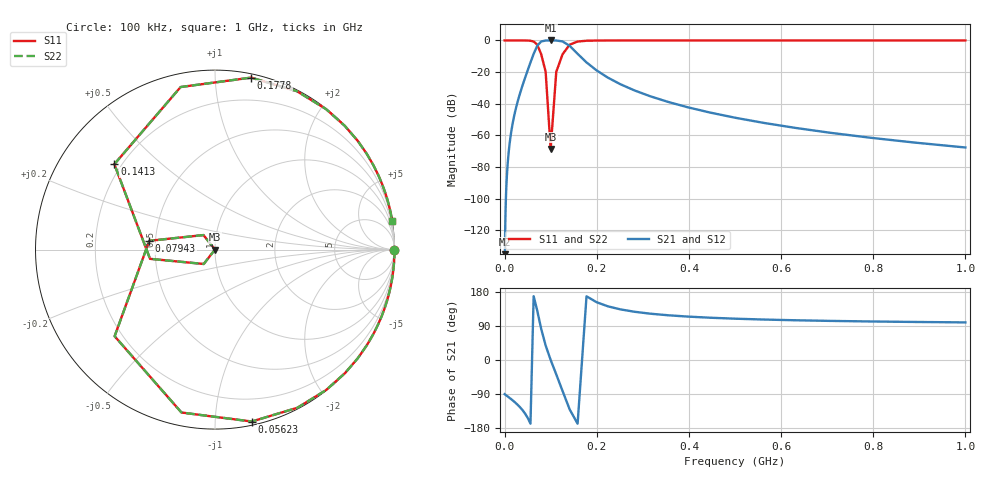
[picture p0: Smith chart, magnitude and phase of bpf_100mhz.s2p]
# Hz S RI R 50
! golden: bpf_100mhz
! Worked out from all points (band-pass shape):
!   81 points, 100 kHz to 1 GHz, reference 50 ohm
!   highest |S21| = 0.00 dB at 100 MHz (marker M1); lowest = -187.9 dB at 100 kHz (marker M2)
!   |S21| within 3 dB of the highest: 72.11 MHz to 139.1 MHz (67.01 MHz wide, 63.4 % of centre)
!   lowest |S11| = -68.5 dB at 100 MHz (marker M3), VSWR 1.00, Z = 50 + j0.0376 ohm
!   |S11| at or under -10 dB: 80.62 MHz to 124.3 MHz (43.72 MHz wide, 42.7 % of centre)
!   |S22| runs from -68.5 to 0.0 dB; largest |S21 - S12| = 0
!   S11 on the Smith chart (normalised r, x): 100 kHz: open; 56.23 MHz: 0.03, -1.24; 79.43 MHz: 0.46, +0.05; 141.3 MHz: 0.17, +0.36; 177.8 MHz: 0.03, +1.23; 1 GHz: 0, +12
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100000  1 -0.00159  -6.39e-13 -4.02e-10  -6.39e-13 -4.02e-10  1 -0.00159
501187.2  1 -0.00797  -4.03e-10 -5.06e-08  -4.03e-10 -5.06e-08  1 -0.00797
2238721  0.9994 -0.0356  -1.61e-07 -4.51e-06  -1.61e-07 -4.51e-06  0.9994 -0.0356
6309573  0.9949 -0.1005  -1.03e-05 -0.000102  -1.03e-05 -0.000102  0.9949 -0.1005
1e7  0.9871 -0.1599  -6.61e-05 -0.000408  -6.61e-05 -0.000408  0.9871 -0.1599
3.162278e7  0.8462 -0.5326  -0.00913 -0.0145  -0.00913 -0.0145  0.8462 -0.5326
3.981072e7  0.7239 -0.6887  -0.0285 -0.0299  -0.0285 -0.0299  0.7239 -0.6887
5.011872e7  0.4588 -0.8813  -0.1003 -0.0522  -0.1003 -0.0522  0.4588 -0.8813
5.623413e7  0.2049 -0.9579  -0.1969 -0.0421  -0.1969 -0.0421  0.2049 -0.9579
6.309573e7  -0.1868 -0.9077  -0.368 0.0757  -0.368 0.0757  -0.1868 -0.9077
7.079458e7  -0.5592 -0.4826  -0.4404 0.5103  -0.4404 0.5103  -0.5592 -0.4826
7.943282e7  -0.3662 0.0489  0.1229 0.9211  0.1229 0.9211  -0.3662 0.0489
8.912509e7  -0.0643 0.081  0.7789 0.6186  0.7789 0.6186  -0.0643 0.081
1e8  -1.27e-06 0.000376  1 0.00339  1 0.00339  -1.27e-06 0.000376
1.122018e8  -0.0627 -0.0801  0.7835 -0.613  0.7835 -0.613  -0.0627 -0.0801
1.258925e8  -0.362 -0.0515  0.1311 -0.9215  0.1311 -0.9215  -0.362 -0.0515
1.412538e8  -0.5607 0.476  -0.4384 -0.5165  -0.4384 -0.5165  -0.5607 0.476
1.584893e8  -0.1915 0.9057  -0.37 -0.0782  -0.37 -0.0782  -0.1915 0.9057
1.778279e8  0.2015 0.9583  -0.1983 0.0417  -0.1983 0.0417  0.2015 0.9583
2.238721e8  0.6176 0.7836  -0.0529 0.0417  -0.0529 0.0417  0.6176 0.7836
3.548134e8  0.8825 0.4701  -0.00538 0.0101  -0.00538 0.0101  0.8825 0.4701
1e9  0.9871 0.1601  -6.65e-05 0.00041  -6.65e-05 0.00041  0.9871 0.1601
